# Generated by FakeRAM 2.0
VERSION 5.7 ;
BUSBITCHARS "[]" ;
PROPERTYDEFINITIONS
  MACRO width INTEGER ;
  MACRO depth INTEGER ;
  MACRO banks INTEGER ;
END PROPERTYDEFINITIONS
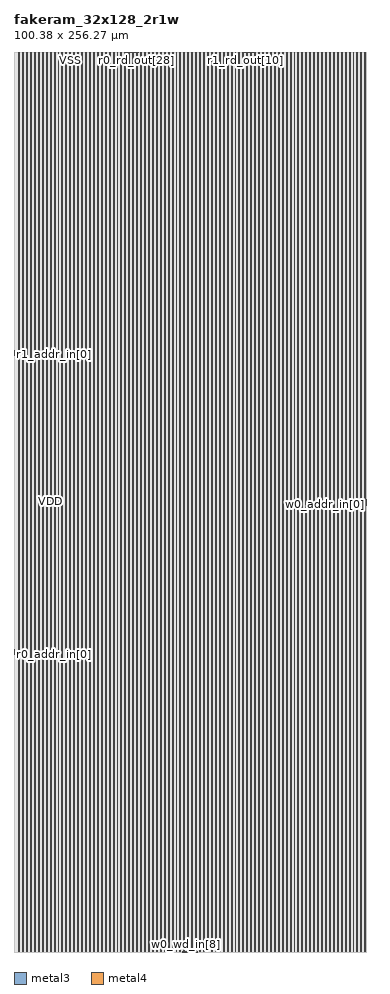
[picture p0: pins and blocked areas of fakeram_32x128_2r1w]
MACRO fakeram_32x128_2r1w
  PROPERTY width 32 ;
  PROPERTY depth 128 ;
  PROPERTY banks 1 ;
  FOREIGN fakeram_32x128_2r1w 0 0 ;
  SYMMETRY X Y R90 ;
  SIZE 100.380 BY 256.270 ;
  CLASS BLOCK ;
  PIN r0_addr_in[0]
    DIRECTION INPUT ;
    USE SIGNAL ;
    SHAPE ABUTMENT ;
    PORT
      LAYER metal3 ;
      RECT 0.000 84.700 0.070 84.770 ;
    END
  END r0_addr_in[0]
  PIN r0_addr_in[1]
    DIRECTION INPUT ;
    USE SIGNAL ;
    SHAPE ABUTMENT ;
    PORT
      LAYER metal3 ;
      RECT 0.000 84.840 0.070 84.910 ;
    END
  END r0_addr_in[1]
  PIN r0_addr_in[2]
    DIRECTION INPUT ;
    USE SIGNAL ;
    SHAPE ABUTMENT ;
    PORT
      LAYER metal3 ;
      RECT 0.000 84.980 0.070 85.050 ;
    END
  END r0_addr_in[2]
  PIN r0_addr_in[3]
    DIRECTION INPUT ;
    USE SIGNAL ;
    SHAPE ABUTMENT ;
    PORT
      LAYER metal3 ;
      RECT 0.000 85.120 0.070 85.190 ;
    END
  END r0_addr_in[3]
  PIN r0_addr_in[4]
    DIRECTION INPUT ;
    USE SIGNAL ;
    SHAPE ABUTMENT ;
    PORT
      LAYER metal3 ;
      RECT 0.000 85.260 0.070 85.330 ;
    END
  END r0_addr_in[4]
  PIN r0_addr_in[5]
    DIRECTION INPUT ;
    USE SIGNAL ;
    SHAPE ABUTMENT ;
    PORT
      LAYER metal3 ;
      RECT 0.000 85.400 0.070 85.470 ;
    END
  END r0_addr_in[5]
  PIN r0_addr_in[6]
    DIRECTION INPUT ;
    USE SIGNAL ;
    SHAPE ABUTMENT ;
    PORT
      LAYER metal3 ;
      RECT 0.000 85.540 0.070 85.610 ;
    END
  END r0_addr_in[6]
  PIN r0_ce_in
    DIRECTION INPUT ;
    USE SIGNAL ;
    SHAPE ABUTMENT ;
    PORT
      LAYER metal3 ;
      RECT 0.000 85.820 0.070 85.890 ;
    END
  END r0_ce_in
  PIN r0_clk
    DIRECTION INPUT ;
    USE SIGNAL ;
    SHAPE ABUTMENT ;
    PORT
      LAYER metal3 ;
      RECT 0.000 85.960 0.070 86.030 ;
    END
  END r0_clk
  PIN r0_rd_out[0]
    DIRECTION OUTPUT ;
    USE SIGNAL ;
    SHAPE ABUTMENT ;
    PORT
      LAYER metal3 ;
      RECT 31.045 256.200 31.115 256.270 ;
    END
  END r0_rd_out[0]
  PIN r0_rd_out[1]
    DIRECTION OUTPUT ;
    USE SIGNAL ;
    SHAPE ABUTMENT ;
    PORT
      LAYER metal3 ;
      RECT 31.185 256.200 31.255 256.270 ;
    END
  END r0_rd_out[1]
  PIN r0_rd_out[2]
    DIRECTION OUTPUT ;
    USE SIGNAL ;
    SHAPE ABUTMENT ;
    PORT
      LAYER metal3 ;
      RECT 31.325 256.200 31.395 256.270 ;
    END
  END r0_rd_out[2]
  PIN r0_rd_out[3]
    DIRECTION OUTPUT ;
    USE SIGNAL ;
    SHAPE ABUTMENT ;
    PORT
      LAYER metal3 ;
      RECT 31.465 256.200 31.535 256.270 ;
    END
  END r0_rd_out[3]
  PIN r0_rd_out[4]
    DIRECTION OUTPUT ;
    USE SIGNAL ;
    SHAPE ABUTMENT ;
    PORT
      LAYER metal3 ;
      RECT 31.605 256.200 31.675 256.270 ;
    END
  END r0_rd_out[4]
  PIN r0_rd_out[5]
    DIRECTION OUTPUT ;
    USE SIGNAL ;
    SHAPE ABUTMENT ;
    PORT
      LAYER metal3 ;
      RECT 31.745 256.200 31.815 256.270 ;
    END
  END r0_rd_out[5]
  PIN r0_rd_out[6]
    DIRECTION OUTPUT ;
    USE SIGNAL ;
    SHAPE ABUTMENT ;
    PORT
      LAYER metal3 ;
      RECT 31.885 256.200 31.955 256.270 ;
    END
  END r0_rd_out[6]
  PIN r0_rd_out[7]
    DIRECTION OUTPUT ;
    USE SIGNAL ;
    SHAPE ABUTMENT ;
    PORT
      LAYER metal3 ;
      RECT 32.025 256.200 32.095 256.270 ;
    END
  END r0_rd_out[7]
  PIN r0_rd_out[8]
    DIRECTION OUTPUT ;
    USE SIGNAL ;
    SHAPE ABUTMENT ;
    PORT
      LAYER metal3 ;
      RECT 32.165 256.200 32.235 256.270 ;
    END
  END r0_rd_out[8]
  PIN r0_rd_out[9]
    DIRECTION OUTPUT ;
    USE SIGNAL ;
    SHAPE ABUTMENT ;
    PORT
      LAYER metal3 ;
      RECT 32.305 256.200 32.375 256.270 ;
    END
  END r0_rd_out[9]
  PIN r0_rd_out[10]
    DIRECTION OUTPUT ;
    USE SIGNAL ;
    SHAPE ABUTMENT ;
    PORT
      LAYER metal3 ;
      RECT 32.445 256.200 32.515 256.270 ;
    END
  END r0_rd_out[10]
  PIN r0_rd_out[11]
    DIRECTION OUTPUT ;
    USE SIGNAL ;
    SHAPE ABUTMENT ;
    PORT
      LAYER metal3 ;
      RECT 32.585 256.200 32.655 256.270 ;
    END
  END r0_rd_out[11]
  PIN r0_rd_out[12]
    DIRECTION OUTPUT ;
    USE SIGNAL ;
    SHAPE ABUTMENT ;
    PORT
      LAYER metal3 ;
      RECT 32.725 256.200 32.795 256.270 ;
    END
  END r0_rd_out[12]
  PIN r0_rd_out[13]
    DIRECTION OUTPUT ;
    USE SIGNAL ;
    SHAPE ABUTMENT ;
    PORT
      LAYER metal3 ;
      RECT 32.865 256.200 32.935 256.270 ;
    END
  END r0_rd_out[13]
  PIN r0_rd_out[14]
    DIRECTION OUTPUT ;
    USE SIGNAL ;
    SHAPE ABUTMENT ;
    PORT
      LAYER metal3 ;
      RECT 33.005 256.200 33.075 256.270 ;
    END
  END r0_rd_out[14]
  PIN r0_rd_out[15]
    DIRECTION OUTPUT ;
    USE SIGNAL ;
    SHAPE ABUTMENT ;
    PORT
      LAYER metal3 ;
      RECT 33.145 256.200 33.215 256.270 ;
    END
  END r0_rd_out[15]
  PIN r0_rd_out[16]
    DIRECTION OUTPUT ;
    USE SIGNAL ;
    SHAPE ABUTMENT ;
    PORT
      LAYER metal3 ;
      RECT 33.285 256.200 33.355 256.270 ;
    END
  END r0_rd_out[16]
  PIN r0_rd_out[17]
    DIRECTION OUTPUT ;
    USE SIGNAL ;
    SHAPE ABUTMENT ;
    PORT
      LAYER metal3 ;
      RECT 33.425 256.200 33.495 256.270 ;
    END
  END r0_rd_out[17]
  PIN r0_rd_out[18]
    DIRECTION OUTPUT ;
    USE SIGNAL ;
    SHAPE ABUTMENT ;
    PORT
      LAYER metal3 ;
      RECT 33.565 256.200 33.635 256.270 ;
    END
  END r0_rd_out[18]
  PIN r0_rd_out[19]
    DIRECTION OUTPUT ;
    USE SIGNAL ;
    SHAPE ABUTMENT ;
    PORT
      LAYER metal3 ;
      RECT 33.705 256.200 33.775 256.270 ;
    END
  END r0_rd_out[19]
  PIN r0_rd_out[20]
    DIRECTION OUTPUT ;
    USE SIGNAL ;
    SHAPE ABUTMENT ;
    PORT
      LAYER metal3 ;
      RECT 33.845 256.200 33.915 256.270 ;
    END
  END r0_rd_out[20]
  PIN r0_rd_out[21]
    DIRECTION OUTPUT ;
    USE SIGNAL ;
    SHAPE ABUTMENT ;
    PORT
      LAYER metal3 ;
      RECT 33.985 256.200 34.055 256.270 ;
    END
  END r0_rd_out[21]
  PIN r0_rd_out[22]
    DIRECTION OUTPUT ;
    USE SIGNAL ;
    SHAPE ABUTMENT ;
    PORT
      LAYER metal3 ;
      RECT 34.125 256.200 34.195 256.270 ;
    END
  END r0_rd_out[22]
  PIN r0_rd_out[23]
    DIRECTION OUTPUT ;
    USE SIGNAL ;
    SHAPE ABUTMENT ;
    PORT
      LAYER metal3 ;
      RECT 34.265 256.200 34.335 256.270 ;
    END
  END r0_rd_out[23]
  PIN r0_rd_out[24]
    DIRECTION OUTPUT ;
    USE SIGNAL ;
    SHAPE ABUTMENT ;
    PORT
      LAYER metal3 ;
      RECT 34.405 256.200 34.475 256.270 ;
    END
  END r0_rd_out[24]
  PIN r0_rd_out[25]
    DIRECTION OUTPUT ;
    USE SIGNAL ;
    SHAPE ABUTMENT ;
    PORT
      LAYER metal3 ;
      RECT 34.545 256.200 34.615 256.270 ;
    END
  END r0_rd_out[25]
  PIN r0_rd_out[26]
    DIRECTION OUTPUT ;
    USE SIGNAL ;
    SHAPE ABUTMENT ;
    PORT
      LAYER metal3 ;
      RECT 34.685 256.200 34.755 256.270 ;
    END
  END r0_rd_out[26]
  PIN r0_rd_out[27]
    DIRECTION OUTPUT ;
    USE SIGNAL ;
    SHAPE ABUTMENT ;
    PORT
      LAYER metal3 ;
      RECT 34.825 256.200 34.895 256.270 ;
    END
  END r0_rd_out[27]
  PIN r0_rd_out[28]
    DIRECTION OUTPUT ;
    USE SIGNAL ;
    SHAPE ABUTMENT ;
    PORT
      LAYER metal3 ;
      RECT 34.965 256.200 35.035 256.270 ;
    END
  END r0_rd_out[28]
  PIN r0_rd_out[29]
    DIRECTION OUTPUT ;
    USE SIGNAL ;
    SHAPE ABUTMENT ;
    PORT
      LAYER metal3 ;
      RECT 35.105 256.200 35.175 256.270 ;
    END
  END r0_rd_out[29]
  PIN r0_rd_out[30]
    DIRECTION OUTPUT ;
    USE SIGNAL ;
    SHAPE ABUTMENT ;
    PORT
      LAYER metal3 ;
      RECT 35.245 256.200 35.315 256.270 ;
    END
  END r0_rd_out[30]
  PIN r0_rd_out[31]
    DIRECTION OUTPUT ;
    USE SIGNAL ;
    SHAPE ABUTMENT ;
    PORT
      LAYER metal3 ;
      RECT 35.385 256.200 35.455 256.270 ;
    END
  END r0_rd_out[31]
  PIN r1_addr_in[0]
    DIRECTION INPUT ;
    USE SIGNAL ;
    SHAPE ABUTMENT ;
    PORT
      LAYER metal3 ;
      RECT 0.000 169.960 0.070 170.030 ;
    END
  END r1_addr_in[0]
  PIN r1_addr_in[1]
    DIRECTION INPUT ;
    USE SIGNAL ;
    SHAPE ABUTMENT ;
    PORT
      LAYER metal3 ;
      RECT 0.000 170.100 0.070 170.170 ;
    END
  END r1_addr_in[1]
  PIN r1_addr_in[2]
    DIRECTION INPUT ;
    USE SIGNAL ;
    SHAPE ABUTMENT ;
    PORT
      LAYER metal3 ;
      RECT 0.000 170.240 0.070 170.310 ;
    END
  END r1_addr_in[2]
  PIN r1_addr_in[3]
    DIRECTION INPUT ;
    USE SIGNAL ;
    SHAPE ABUTMENT ;
    PORT
      LAYER metal3 ;
      RECT 0.000 170.380 0.070 170.450 ;
    END
  END r1_addr_in[3]
  PIN r1_addr_in[4]
    DIRECTION INPUT ;
    USE SIGNAL ;
    SHAPE ABUTMENT ;
    PORT
      LAYER metal3 ;
      RECT 0.000 170.520 0.070 170.590 ;
    END
  END r1_addr_in[4]
  PIN r1_addr_in[5]
    DIRECTION INPUT ;
    USE SIGNAL ;
    SHAPE ABUTMENT ;
    PORT
      LAYER metal3 ;
      RECT 0.000 170.660 0.070 170.730 ;
    END
  END r1_addr_in[5]
  PIN r1_addr_in[6]
    DIRECTION INPUT ;
    USE SIGNAL ;
    SHAPE ABUTMENT ;
    PORT
      LAYER metal3 ;
      RECT 0.000 170.800 0.070 170.870 ;
    END
  END r1_addr_in[6]
  PIN r1_ce_in
    DIRECTION INPUT ;
    USE SIGNAL ;
    SHAPE ABUTMENT ;
    PORT
      LAYER metal3 ;
      RECT 0.000 171.080 0.070 171.150 ;
    END
  END r1_ce_in
  PIN r1_clk
    DIRECTION INPUT ;
    USE SIGNAL ;
    SHAPE ABUTMENT ;
    PORT
      LAYER metal3 ;
      RECT 0.000 171.220 0.070 171.290 ;
    END
  END r1_clk
  PIN r1_rd_out[0]
    DIRECTION OUTPUT ;
    USE SIGNAL ;
    SHAPE ABUTMENT ;
    PORT
      LAYER metal3 ;
      RECT 64.365 256.200 64.435 256.270 ;
    END
  END r1_rd_out[0]
  PIN r1_rd_out[1]
    DIRECTION OUTPUT ;
    USE SIGNAL ;
    SHAPE ABUTMENT ;
    PORT
      LAYER metal3 ;
      RECT 64.505 256.200 64.575 256.270 ;
    END
  END r1_rd_out[1]
  PIN r1_rd_out[2]
    DIRECTION OUTPUT ;
    USE SIGNAL ;
    SHAPE ABUTMENT ;
    PORT
      LAYER metal3 ;
      RECT 64.645 256.200 64.715 256.270 ;
    END
  END r1_rd_out[2]
  PIN r1_rd_out[3]
    DIRECTION OUTPUT ;
    USE SIGNAL ;
    SHAPE ABUTMENT ;
    PORT
      LAYER metal3 ;
      RECT 64.785 256.200 64.855 256.270 ;
    END
  END r1_rd_out[3]
  PIN r1_rd_out[4]
    DIRECTION OUTPUT ;
    USE SIGNAL ;
    SHAPE ABUTMENT ;
    PORT
      LAYER metal3 ;
      RECT 64.925 256.200 64.995 256.270 ;
    END
  END r1_rd_out[4]
  PIN r1_rd_out[5]
    DIRECTION OUTPUT ;
    USE SIGNAL ;
    SHAPE ABUTMENT ;
    PORT
      LAYER metal3 ;
      RECT 65.065 256.200 65.135 256.270 ;
    END
  END r1_rd_out[5]
  PIN r1_rd_out[6]
    DIRECTION OUTPUT ;
    USE SIGNAL ;
    SHAPE ABUTMENT ;
    PORT
      LAYER metal3 ;
      RECT 65.205 256.200 65.275 256.270 ;
    END
  END r1_rd_out[6]
  PIN r1_rd_out[7]
    DIRECTION OUTPUT ;
    USE SIGNAL ;
    SHAPE ABUTMENT ;
    PORT
      LAYER metal3 ;
      RECT 65.345 256.200 65.415 256.270 ;
    END
  END r1_rd_out[7]
  PIN r1_rd_out[8]
    DIRECTION OUTPUT ;
    USE SIGNAL ;
    SHAPE ABUTMENT ;
    PORT
      LAYER metal3 ;
      RECT 65.485 256.200 65.555 256.270 ;
    END
  END r1_rd_out[8]
  PIN r1_rd_out[9]
    DIRECTION OUTPUT ;
    USE SIGNAL ;
    SHAPE ABUTMENT ;
    PORT
      LAYER metal3 ;
      RECT 65.625 256.200 65.695 256.270 ;
    END
  END r1_rd_out[9]
  PIN r1_rd_out[10]
    DIRECTION OUTPUT ;
    USE SIGNAL ;
    SHAPE ABUTMENT ;
    PORT
      LAYER metal3 ;
      RECT 65.765 256.200 65.835 256.270 ;
    END
  END r1_rd_out[10]
  PIN r1_rd_out[11]
    DIRECTION OUTPUT ;
    USE SIGNAL ;
    SHAPE ABUTMENT ;
    PORT
      LAYER metal3 ;
      RECT 65.905 256.200 65.975 256.270 ;
    END
  END r1_rd_out[11]
  PIN r1_rd_out[12]
    DIRECTION OUTPUT ;
    USE SIGNAL ;
    SHAPE ABUTMENT ;
    PORT
      LAYER metal3 ;
      RECT 66.045 256.200 66.115 256.270 ;
    END
  END r1_rd_out[12]
  PIN r1_rd_out[13]
    DIRECTION OUTPUT ;
    USE SIGNAL ;
    SHAPE ABUTMENT ;
    PORT
      LAYER metal3 ;
      RECT 66.185 256.200 66.255 256.270 ;
    END
  END r1_rd_out[13]
  PIN r1_rd_out[14]
    DIRECTION OUTPUT ;
    USE SIGNAL ;
    SHAPE ABUTMENT ;
    PORT
      LAYER metal3 ;
      RECT 66.325 256.200 66.395 256.270 ;
    END
  END r1_rd_out[14]
  PIN r1_rd_out[15]
    DIRECTION OUTPUT ;
    USE SIGNAL ;
    SHAPE ABUTMENT ;
    PORT
      LAYER metal3 ;
      RECT 66.465 256.200 66.535 256.270 ;
    END
  END r1_rd_out[15]
  PIN r1_rd_out[16]
    DIRECTION OUTPUT ;
    USE SIGNAL ;
    SHAPE ABUTMENT ;
    PORT
      LAYER metal3 ;
      RECT 66.605 256.200 66.675 256.270 ;
    END
  END r1_rd_out[16]
  PIN r1_rd_out[17]
    DIRECTION OUTPUT ;
    USE SIGNAL ;
    SHAPE ABUTMENT ;
    PORT
      LAYER metal3 ;
      RECT 66.745 256.200 66.815 256.270 ;
    END
  END r1_rd_out[17]
  PIN r1_rd_out[18]
    DIRECTION OUTPUT ;
    USE SIGNAL ;
    SHAPE ABUTMENT ;
    PORT
      LAYER metal3 ;
      RECT 66.885 256.200 66.955 256.270 ;
    END
  END r1_rd_out[18]
  PIN r1_rd_out[19]
    DIRECTION OUTPUT ;
    USE SIGNAL ;
    SHAPE ABUTMENT ;
    PORT
      LAYER metal3 ;
      RECT 67.025 256.200 67.095 256.270 ;
    END
  END r1_rd_out[19]
  PIN r1_rd_out[20]
    DIRECTION OUTPUT ;
    USE SIGNAL ;
    SHAPE ABUTMENT ;
    PORT
      LAYER metal3 ;
      RECT 67.165 256.200 67.235 256.270 ;
    END
  END r1_rd_out[20]
  PIN r1_rd_out[21]
    DIRECTION OUTPUT ;
    USE SIGNAL ;
    SHAPE ABUTMENT ;
    PORT
      LAYER metal3 ;
      RECT 67.305 256.200 67.375 256.270 ;
    END
  END r1_rd_out[21]
  PIN r1_rd_out[22]
    DIRECTION OUTPUT ;
    USE SIGNAL ;
    SHAPE ABUTMENT ;
    PORT
      LAYER metal3 ;
      RECT 67.445 256.200 67.515 256.270 ;
    END
  END r1_rd_out[22]
  PIN r1_rd_out[23]
    DIRECTION OUTPUT ;
    USE SIGNAL ;
    SHAPE ABUTMENT ;
    PORT
      LAYER metal3 ;
      RECT 67.585 256.200 67.655 256.270 ;
    END
  END r1_rd_out[23]
  PIN r1_rd_out[24]
    DIRECTION OUTPUT ;
    USE SIGNAL ;
    SHAPE ABUTMENT ;
    PORT
      LAYER metal3 ;
      RECT 67.725 256.200 67.795 256.270 ;
    END
  END r1_rd_out[24]
  PIN r1_rd_out[25]
    DIRECTION OUTPUT ;
    USE SIGNAL ;
    SHAPE ABUTMENT ;
    PORT
      LAYER metal3 ;
      RECT 67.865 256.200 67.935 256.270 ;
    END
  END r1_rd_out[25]
  PIN r1_rd_out[26]
    DIRECTION OUTPUT ;
    USE SIGNAL ;
    SHAPE ABUTMENT ;
    PORT
      LAYER metal3 ;
      RECT 68.005 256.200 68.075 256.270 ;
    END
  END r1_rd_out[26]
  PIN r1_rd_out[27]
    DIRECTION OUTPUT ;
    USE SIGNAL ;
    SHAPE ABUTMENT ;
    PORT
      LAYER metal3 ;
      RECT 68.145 256.200 68.215 256.270 ;
    END
  END r1_rd_out[27]
  PIN r1_rd_out[28]
    DIRECTION OUTPUT ;
    USE SIGNAL ;
    SHAPE ABUTMENT ;
    PORT
      LAYER metal3 ;
      RECT 68.285 256.200 68.355 256.270 ;
    END
  END r1_rd_out[28]
  PIN r1_rd_out[29]
    DIRECTION OUTPUT ;
    USE SIGNAL ;
    SHAPE ABUTMENT ;
    PORT
      LAYER metal3 ;
      RECT 68.425 256.200 68.495 256.270 ;
    END
  END r1_rd_out[29]
  PIN r1_rd_out[30]
    DIRECTION OUTPUT ;
    USE SIGNAL ;
    SHAPE ABUTMENT ;
    PORT
      LAYER metal3 ;
      RECT 68.565 256.200 68.635 256.270 ;
    END
  END r1_rd_out[30]
  PIN r1_rd_out[31]
    DIRECTION OUTPUT ;
    USE SIGNAL ;
    SHAPE ABUTMENT ;
    PORT
      LAYER metal3 ;
      RECT 68.705 256.200 68.775 256.270 ;
    END
  END r1_rd_out[31]
  PIN w0_addr_in[0]
    DIRECTION INPUT ;
    USE SIGNAL ;
    SHAPE ABUTMENT ;
    PORT
      LAYER metal3 ;
      RECT 100.310 127.260 100.380 127.330 ;
    END
  END w0_addr_in[0]
  PIN w0_addr_in[1]
    DIRECTION INPUT ;
    USE SIGNAL ;
    SHAPE ABUTMENT ;
    PORT
      LAYER metal3 ;
      RECT 100.310 127.400 100.380 127.470 ;
    END
  END w0_addr_in[1]
  PIN w0_addr_in[2]
    DIRECTION INPUT ;
    USE SIGNAL ;
    SHAPE ABUTMENT ;
    PORT
      LAYER metal3 ;
      RECT 100.310 127.540 100.380 127.610 ;
    END
  END w0_addr_in[2]
  PIN w0_addr_in[3]
    DIRECTION INPUT ;
    USE SIGNAL ;
    SHAPE ABUTMENT ;
    PORT
      LAYER metal3 ;
      RECT 100.310 127.680 100.380 127.750 ;
    END
  END w0_addr_in[3]
  PIN w0_addr_in[4]
    DIRECTION INPUT ;
    USE SIGNAL ;
    SHAPE ABUTMENT ;
    PORT
      LAYER metal3 ;
      RECT 100.310 127.820 100.380 127.890 ;
    END
  END w0_addr_in[4]
  PIN w0_addr_in[5]
    DIRECTION INPUT ;
    USE SIGNAL ;
    SHAPE ABUTMENT ;
    PORT
      LAYER metal3 ;
      RECT 100.310 127.960 100.380 128.030 ;
    END
  END w0_addr_in[5]
  PIN w0_addr_in[6]
    DIRECTION INPUT ;
    USE SIGNAL ;
    SHAPE ABUTMENT ;
    PORT
      LAYER metal3 ;
      RECT 100.310 128.100 100.380 128.170 ;
    END
  END w0_addr_in[6]
  PIN w0_we_in
    DIRECTION INPUT ;
    USE SIGNAL ;
    SHAPE ABUTMENT ;
    PORT
      LAYER metal3 ;
      RECT 100.310 128.380 100.380 128.450 ;
    END
  END w0_we_in
  PIN w0_ce_in
    DIRECTION INPUT ;
    USE SIGNAL ;
    SHAPE ABUTMENT ;
    PORT
      LAYER metal3 ;
      RECT 100.310 128.520 100.380 128.590 ;
    END
  END w0_ce_in
  PIN w0_clk
    DIRECTION INPUT ;
    USE SIGNAL ;
    SHAPE ABUTMENT ;
    PORT
      LAYER metal3 ;
      RECT 100.310 128.660 100.380 128.730 ;
    END
  END w0_clk
  PIN w0_wd_in[0]
    DIRECTION INPUT ;
    USE SIGNAL ;
    SHAPE ABUTMENT ;
    PORT
      LAYER metal3 ;
      RECT 47.845 0.000 47.915 0.070 ;
    END
  END w0_wd_in[0]
  PIN w0_wd_in[1]
    DIRECTION INPUT ;
    USE SIGNAL ;
    SHAPE ABUTMENT ;
    PORT
      LAYER metal3 ;
      RECT 47.985 0.000 48.055 0.070 ;
    END
  END w0_wd_in[1]
  PIN w0_wd_in[2]
    DIRECTION INPUT ;
    USE SIGNAL ;
    SHAPE ABUTMENT ;
    PORT
      LAYER metal3 ;
      RECT 48.125 0.000 48.195 0.070 ;
    END
  END w0_wd_in[2]
  PIN w0_wd_in[3]
    DIRECTION INPUT ;
    USE SIGNAL ;
    SHAPE ABUTMENT ;
    PORT
      LAYER metal3 ;
      RECT 48.265 0.000 48.335 0.070 ;
    END
  END w0_wd_in[3]
  PIN w0_wd_in[4]
    DIRECTION INPUT ;
    USE SIGNAL ;
    SHAPE ABUTMENT ;
    PORT
      LAYER metal3 ;
      RECT 48.405 0.000 48.475 0.070 ;
    END
  END w0_wd_in[4]
  PIN w0_wd_in[5]
    DIRECTION INPUT ;
    USE SIGNAL ;
    SHAPE ABUTMENT ;
    PORT
      LAYER metal3 ;
      RECT 48.545 0.000 48.615 0.070 ;
    END
  END w0_wd_in[5]
  PIN w0_wd_in[6]
    DIRECTION INPUT ;
    USE SIGNAL ;
    SHAPE ABUTMENT ;
    PORT
      LAYER metal3 ;
      RECT 48.685 0.000 48.755 0.070 ;
    END
  END w0_wd_in[6]
  PIN w0_wd_in[7]
    DIRECTION INPUT ;
    USE SIGNAL ;
    SHAPE ABUTMENT ;
    PORT
      LAYER metal3 ;
      RECT 48.825 0.000 48.895 0.070 ;
    END
  END w0_wd_in[7]
  PIN w0_wd_in[8]
    DIRECTION INPUT ;
    USE SIGNAL ;
    SHAPE ABUTMENT ;
    PORT
      LAYER metal3 ;
      RECT 48.965 0.000 49.035 0.070 ;
    END
  END w0_wd_in[8]
  PIN w0_wd_in[9]
    DIRECTION INPUT ;
    USE SIGNAL ;
    SHAPE ABUTMENT ;
    PORT
      LAYER metal3 ;
      RECT 49.105 0.000 49.175 0.070 ;
    END
  END w0_wd_in[9]
  PIN w0_wd_in[10]
    DIRECTION INPUT ;
    USE SIGNAL ;
    SHAPE ABUTMENT ;
    PORT
      LAYER metal3 ;
      RECT 49.245 0.000 49.315 0.070 ;
    END
  END w0_wd_in[10]
  PIN w0_wd_in[11]
    DIRECTION INPUT ;
    USE SIGNAL ;
    SHAPE ABUTMENT ;
    PORT
      LAYER metal3 ;
      RECT 49.385 0.000 49.455 0.070 ;
    END
  END w0_wd_in[11]
  PIN w0_wd_in[12]
    DIRECTION INPUT ;
    USE SIGNAL ;
    SHAPE ABUTMENT ;
    PORT
      LAYER metal3 ;
      RECT 49.525 0.000 49.595 0.070 ;
    END
  END w0_wd_in[12]
  PIN w0_wd_in[13]
    DIRECTION INPUT ;
    USE SIGNAL ;
    SHAPE ABUTMENT ;
    PORT
      LAYER metal3 ;
      RECT 49.665 0.000 49.735 0.070 ;
    END
  END w0_wd_in[13]
  PIN w0_wd_in[14]
    DIRECTION INPUT ;
    USE SIGNAL ;
    SHAPE ABUTMENT ;
    PORT
      LAYER metal3 ;
      RECT 49.805 0.000 49.875 0.070 ;
    END
  END w0_wd_in[14]
  PIN w0_wd_in[15]
    DIRECTION INPUT ;
    USE SIGNAL ;
    SHAPE ABUTMENT ;
    PORT
      LAYER metal3 ;
      RECT 49.945 0.000 50.015 0.070 ;
    END
  END w0_wd_in[15]
  PIN w0_wd_in[16]
    DIRECTION INPUT ;
    USE SIGNAL ;
    SHAPE ABUTMENT ;
    PORT
      LAYER metal3 ;
      RECT 50.085 0.000 50.155 0.070 ;
    END
  END w0_wd_in[16]
  PIN w0_wd_in[17]
    DIRECTION INPUT ;
    USE SIGNAL ;
    SHAPE ABUTMENT ;
    PORT
      LAYER metal3 ;
      RECT 50.225 0.000 50.295 0.070 ;
    END
  END w0_wd_in[17]
  PIN w0_wd_in[18]
    DIRECTION INPUT ;
    USE SIGNAL ;
    SHAPE ABUTMENT ;
    PORT
      LAYER metal3 ;
      RECT 50.365 0.000 50.435 0.070 ;
    END
  END w0_wd_in[18]
  PIN w0_wd_in[19]
    DIRECTION INPUT ;
    USE SIGNAL ;
    SHAPE ABUTMENT ;
    PORT
      LAYER metal3 ;
      RECT 50.505 0.000 50.575 0.070 ;
    END
  END w0_wd_in[19]
  PIN w0_wd_in[20]
    DIRECTION INPUT ;
    USE SIGNAL ;
    SHAPE ABUTMENT ;
    PORT
      LAYER metal3 ;
      RECT 50.645 0.000 50.715 0.070 ;
    END
  END w0_wd_in[20]
  PIN w0_wd_in[21]
    DIRECTION INPUT ;
    USE SIGNAL ;
    SHAPE ABUTMENT ;
    PORT
      LAYER metal3 ;
      RECT 50.785 0.000 50.855 0.070 ;
    END
  END w0_wd_in[21]
  PIN w0_wd_in[22]
    DIRECTION INPUT ;
    USE SIGNAL ;
    SHAPE ABUTMENT ;
    PORT
      LAYER metal3 ;
      RECT 50.925 0.000 50.995 0.070 ;
    END
  END w0_wd_in[22]
  PIN w0_wd_in[23]
    DIRECTION INPUT ;
    USE SIGNAL ;
    SHAPE ABUTMENT ;
    PORT
      LAYER metal3 ;
      RECT 51.065 0.000 51.135 0.070 ;
    END
  END w0_wd_in[23]
  PIN w0_wd_in[24]
    DIRECTION INPUT ;
    USE SIGNAL ;
    SHAPE ABUTMENT ;
    PORT
      LAYER metal3 ;
      RECT 51.205 0.000 51.275 0.070 ;
    END
  END w0_wd_in[24]
  PIN w0_wd_in[25]
    DIRECTION INPUT ;
    USE SIGNAL ;
    SHAPE ABUTMENT ;
    PORT
      LAYER metal3 ;
      RECT 51.345 0.000 51.415 0.070 ;
    END
  END w0_wd_in[25]
  PIN w0_wd_in[26]
    DIRECTION INPUT ;
    USE SIGNAL ;
    SHAPE ABUTMENT ;
    PORT
      LAYER metal3 ;
      RECT 51.485 0.000 51.555 0.070 ;
    END
  END w0_wd_in[26]
  PIN w0_wd_in[27]
    DIRECTION INPUT ;
    USE SIGNAL ;
    SHAPE ABUTMENT ;
    PORT
      LAYER metal3 ;
      RECT 51.625 0.000 51.695 0.070 ;
    END
  END w0_wd_in[27]
  PIN w0_wd_in[28]
    DIRECTION INPUT ;
    USE SIGNAL ;
    SHAPE ABUTMENT ;
    PORT
      LAYER metal3 ;
      RECT 51.765 0.000 51.835 0.070 ;
    END
  END w0_wd_in[28]
  PIN w0_wd_in[29]
    DIRECTION INPUT ;
    USE SIGNAL ;
    SHAPE ABUTMENT ;
    PORT
      LAYER metal3 ;
      RECT 51.905 0.000 51.975 0.070 ;
    END
  END w0_wd_in[29]
  PIN w0_wd_in[30]
    DIRECTION INPUT ;
    USE SIGNAL ;
    SHAPE ABUTMENT ;
    PORT
      LAYER metal3 ;
      RECT 52.045 0.000 52.115 0.070 ;
    END
  END w0_wd_in[30]
  PIN w0_wd_in[31]
    DIRECTION INPUT ;
    USE SIGNAL ;
    SHAPE ABUTMENT ;
    PORT
      LAYER metal3 ;
      RECT 52.185 0.000 52.255 0.070 ;
    END
  END w0_wd_in[31]
  PIN VSS
    DIRECTION INOUT ;
    USE GROUND ;
    PORT
      LAYER metal4 ;
      RECT 2.450 0.140 2.730 256.130 ;
      RECT 4.690 0.140 4.970 256.130 ;
      RECT 6.930 0.140 7.210 256.130 ;
      RECT 9.170 0.140 9.450 256.130 ;
      RECT 11.410 0.140 11.690 256.130 ;
      RECT 13.650 0.140 13.930 256.130 ;
      RECT 15.890 0.140 16.170 256.130 ;
      RECT 18.130 0.140 18.410 256.130 ;
      RECT 20.370 0.140 20.650 256.130 ;
      RECT 22.610 0.140 22.890 256.130 ;
      RECT 24.850 0.140 25.130 256.130 ;
      RECT 27.090 0.140 27.370 256.130 ;
      RECT 29.330 0.140 29.610 256.130 ;
      RECT 31.570 0.140 31.850 256.130 ;
      RECT 33.810 0.140 34.090 256.130 ;
      RECT 36.050 0.140 36.330 256.130 ;
      RECT 38.290 0.140 38.570 256.130 ;
      RECT 40.530 0.140 40.810 256.130 ;
      RECT 42.770 0.140 43.050 256.130 ;
      RECT 45.010 0.140 45.290 256.130 ;
      RECT 47.250 0.140 47.530 256.130 ;
      RECT 49.490 0.140 49.770 256.130 ;
      RECT 51.730 0.140 52.010 256.130 ;
      RECT 53.970 0.140 54.250 256.130 ;
      RECT 56.210 0.140 56.490 256.130 ;
      RECT 58.450 0.140 58.730 256.130 ;
      RECT 60.690 0.140 60.970 256.130 ;
      RECT 62.930 0.140 63.210 256.130 ;
      RECT 65.170 0.140 65.450 256.130 ;
      RECT 67.410 0.140 67.690 256.130 ;
      RECT 69.650 0.140 69.930 256.130 ;
      RECT 71.890 0.140 72.170 256.130 ;
      RECT 74.130 0.140 74.410 256.130 ;
      RECT 76.370 0.140 76.650 256.130 ;
      RECT 78.610 0.140 78.890 256.130 ;
      RECT 80.850 0.140 81.130 256.130 ;
      RECT 83.090 0.140 83.370 256.130 ;
      RECT 85.330 0.140 85.610 256.130 ;
      RECT 87.570 0.140 87.850 256.130 ;
      RECT 89.810 0.140 90.090 256.130 ;
      RECT 92.050 0.140 92.330 256.130 ;
      RECT 94.290 0.140 94.570 256.130 ;
      RECT 96.530 0.140 96.810 256.130 ;
      RECT 98.770 0.140 99.050 256.130 ;
    END
  END VSS
  PIN VDD
    DIRECTION INOUT ;
    USE POWER ;
    PORT
      LAYER metal4 ;
      RECT 1.330 0.140 1.610 256.130 ;
      RECT 3.570 0.140 3.850 256.130 ;
      RECT 5.810 0.140 6.090 256.130 ;
      RECT 8.050 0.140 8.330 256.130 ;
      RECT 10.290 0.140 10.570 256.130 ;
      RECT 12.530 0.140 12.810 256.130 ;
      RECT 14.770 0.140 15.050 256.130 ;
      RECT 17.010 0.140 17.290 256.130 ;
      RECT 19.250 0.140 19.530 256.130 ;
      RECT 21.490 0.140 21.770 256.130 ;
      RECT 23.730 0.140 24.010 256.130 ;
      RECT 25.970 0.140 26.250 256.130 ;
      RECT 28.210 0.140 28.490 256.130 ;
      RECT 30.450 0.140 30.730 256.130 ;
      RECT 32.690 0.140 32.970 256.130 ;
      RECT 34.930 0.140 35.210 256.130 ;
      RECT 37.170 0.140 37.450 256.130 ;
      RECT 39.410 0.140 39.690 256.130 ;
      RECT 41.650 0.140 41.930 256.130 ;
      RECT 43.890 0.140 44.170 256.130 ;
      RECT 46.130 0.140 46.410 256.130 ;
      RECT 48.370 0.140 48.650 256.130 ;
      RECT 50.610 0.140 50.890 256.130 ;
      RECT 52.850 0.140 53.130 256.130 ;
      RECT 55.090 0.140 55.370 256.130 ;
      RECT 57.330 0.140 57.610 256.130 ;
      RECT 59.570 0.140 59.850 256.130 ;
      RECT 61.810 0.140 62.090 256.130 ;
      RECT 64.050 0.140 64.330 256.130 ;
      RECT 66.290 0.140 66.570 256.130 ;
      RECT 68.530 0.140 68.810 256.130 ;
      RECT 70.770 0.140 71.050 256.130 ;
      RECT 73.010 0.140 73.290 256.130 ;
      RECT 75.250 0.140 75.530 256.130 ;
      RECT 77.490 0.140 77.770 256.130 ;
      RECT 79.730 0.140 80.010 256.130 ;
      RECT 81.970 0.140 82.250 256.130 ;
      RECT 84.210 0.140 84.490 256.130 ;
      RECT 86.450 0.140 86.730 256.130 ;
      RECT 88.690 0.140 88.970 256.130 ;
      RECT 90.930 0.140 91.210 256.130 ;
      RECT 93.170 0.140 93.450 256.130 ;
      RECT 95.410 0.140 95.690 256.130 ;
      RECT 97.650 0.140 97.930 256.130 ;
      RECT 99.890 0.140 100.170 256.130 ;
    END
  END VDD
  OBS
    LAYER metal1 ;
    RECT 0 0 100.380 256.270 ;
    LAYER metal2 ;
    RECT 0 0 100.380 256.270 ;
    LAYER metal3 ;
    RECT 0 0 100.380 256.270 ;
    LAYER metal4 ;
    RECT 0 0 100.380 256.270 ;
    LAYER OVERLAP ;
    RECT 0 0 100.380 256.270 ;
  END
END fakeram_32x128_2r1w

END LIBRARY
